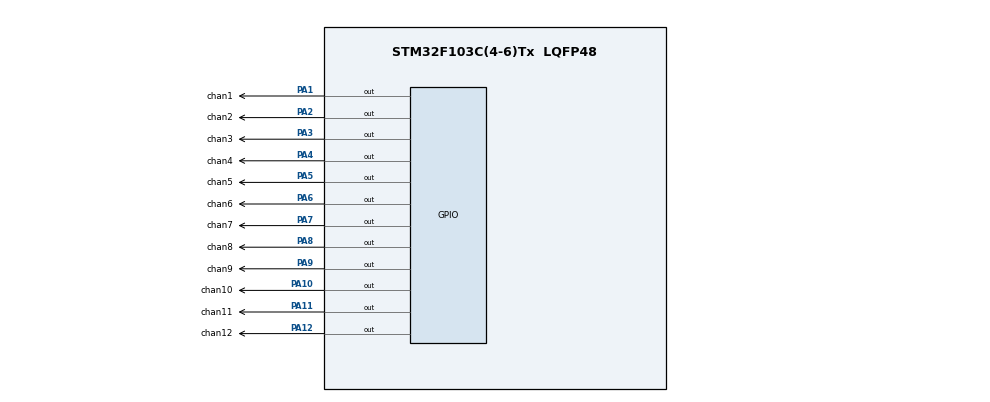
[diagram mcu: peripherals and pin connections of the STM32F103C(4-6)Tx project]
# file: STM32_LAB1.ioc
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Mcu.Family=STM32F1
Mcu.Name=STM32F103C(4-6)Tx
Mcu.Package=LQFP48
NVIC.PriorityGroup=NVIC_PRIORITYGROUP_4
PA1.GPIO_Label=chan1
PA1.Signal=GPIO_Output
PA10.GPIO_Label=chan10
PA10.Signal=GPIO_Output
PA11.GPIO_Label=chan11
PA11.Signal=GPIO_Output
PA12.GPIO_Label=chan12
PA12.Signal=GPIO_Output
PA2.GPIO_Label=chan2
PA2.Signal=GPIO_Output
PA3.GPIO_Label=chan3
PA3.Signal=GPIO_Output
PA4.GPIO_Label=chan4
PA4.Signal=GPIO_Output
PA5.GPIO_Label=chan5
PA5.Signal=GPIO_Output
PA6.GPIO_Label=chan6
PA6.Signal=GPIO_Output
PA7.GPIO_Label=chan7
PA7.Signal=GPIO_Output
PA8.GPIO_Label=chan8
PA8.Signal=GPIO_Output
PA9.GPIO_Label=chan9
PA9.Signal=GPIO_Output
ProjectManager.HeapSize=0x200
ProjectManager.StackSize=0x400
ProjectManager.TargetToolchain=STM32CubeIDE
RCC.APB1Freq_Value=8000000
RCC.APB2Freq_Value=8000000
board=custom

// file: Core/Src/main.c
/* USER CODE BEGIN Header */
/**
  ******************************************************************************
  * @file           : main.c
  * @brief          : Main program body
  ******************************************************************************
  * @attention
  *
  * Copyright (c) 2023 STMicroelectronics.
  * All rights reserved.
  *
  * This software is licensed under terms that can be found in the LICENSE file
  * in the root directory of this software component.
  * If no LICENSE file comes with this software, it is provided AS-IS.
  *
  ******************************************************************************
  */
/* USER CODE END Header */
#include "main.h"

void SystemClock_Config(void);
static void MX_GPIO_Init(void);

int main(void)
{

  /* MCU Configuration--------------------------------------------------------*/

  /* Reset of all peripherals, Initializes the Flash interface and the Systick. */
  HAL_Init();

  /* Configure the system clock */
  SystemClock_Config();

  /* Initialize all configured peripherals */
  MX_GPIO_Init();
  /* USER CODE BEGIN 2 */
  void do1()
{HAL_GPIO_WritePin(led_red1_GPIO_Port, led_red1_Pin,RESET);
 HAL_GPIO_WritePin(led_green1_GPIO_Port, led_green1_Pin,SET);
 HAL_GPIO_WritePin(led_yellow1_GPIO_Port, led_yellow1_Pin,SET);}
  void xanh1()
{
HAL_GPIO_WritePin(led_red1_GPIO_Port, led_red1_Pin,SET);
HAL_GPIO_WritePin(led_green1_GPIO_Port, led_green1_Pin,RESET);
HAL_GPIO_WritePin(led_yellow1_GPIO_Port, led_yellow1_Pin,SET);
}
  void vang1()
{HAL_GPIO_WritePin(led_red1_GPIO_Port, led_red1_Pin,SET);
 HAL_GPIO_WritePin(led_green1_GPIO_Port, led_green1_Pin,SET);
 HAL_GPIO_WritePin(led_yellow1_GPIO_Port, led_yellow1_Pin,RESET);
}
  void do2()
{HAL_GPIO_WritePin(led_red2_GPIO_Port, led_red2_Pin,RESET);
 HAL_GPIO_WritePin(led_green2_GPIO_Port, led_green2_Pin,SET);
 HAL_GPIO_WritePin(led_yellow2_GPIO_Port, led_yellow2_Pin,SET);}
  void xanh2()
{
HAL_GPIO_WritePin(led_red2_GPIO_Port, led_red2_Pin,SET);
HAL_GPIO_WritePin(led_green2_GPIO_Port, led_green2_Pin,RESET);
HAL_GPIO_WritePin(led_yellow2_GPIO_Port, led_yellow2_Pin,SET);
}
  void vang2()
{HAL_GPIO_WritePin(led_red2_GPIO_Port, led_red2_Pin,SET);
 HAL_GPIO_WritePin(led_green2_GPIO_Port, led_green2_Pin,SET);
 HAL_GPIO_WritePin(led_yellow2_GPIO_Port, led_yellow2_Pin,RESET);
}
  void display7SEGa(int n)
  {
  	switch (n)
  	{
  	case 0 :
  		HAL_GPIO_WritePin(chan1a_GPIO_Port,chan1a_Pin, RESET);
  		HAL_GPIO_WritePin(chan1b_GPIO_Port,chan1b_Pin, RESET);
  		HAL_GPIO_WritePin(chan1c_GPIO_Port,chan1c_Pin, RESET);
  		HAL_GPIO_WritePin(chan1d_GPIO_Port,chan1d_Pin, RESET);
  		HAL_GPIO_WritePin(chan1e_GPIO_Port,chan1e_Pin, RESET);
  		HAL_GPIO_WritePin(chan1f_GPIO_Port,chan1f_Pin, RESET);
  		HAL_GPIO_WritePin(chan1g_GPIO_Port,chan1g_Pin, SET);
  	    break ;
  	case 1 :
  		HAL_GPIO_WritePin(chan1a_GPIO_Port,chan1a_Pin, SET);
  		HAL_GPIO_WritePin(chan1b_GPIO_Port,chan1b_Pin, RESET);
  		HAL_GPIO_WritePin(chan1c_GPIO_Port,chan1c_Pin, RESET);
  		HAL_GPIO_WritePin(chan1d_GPIO_Port,chan1d_Pin, SET);
  		HAL_GPIO_WritePin(chan1e_GPIO_Port,chan1e_Pin, SET);
  		HAL_GPIO_WritePin(chan1f_GPIO_Port,chan1f_Pin, SET);
  		HAL_GPIO_WritePin(chan1g_GPIO_Port,chan1g_Pin, SET);
  	    break;
  	case 2 :
  		HAL_GPIO_WritePin(chan1a_GPIO_Port,chan1a_Pin, RESET);
  		HAL_GPIO_WritePin(chan1b_GPIO_Port,chan1b_Pin, RESET);
  		HAL_GPIO_WritePin(chan1c_GPIO_Port,chan1c_Pin, SET);
  		HAL_GPIO_WritePin(chan1d_GPIO_Port,chan1d_Pin, RESET);
  		HAL_GPIO_WritePin(chan1e_GPIO_Port,chan1e_Pin, RESET);
  		HAL_GPIO_WritePin(chan1f_GPIO_Port,chan1f_Pin, SET);
  		HAL_GPIO_WritePin(chan1g_GPIO_Port,chan1g_Pin, RESET);
  	    break ;
  	case 3 :
  		HAL_GPIO_WritePin(chan1a_GPIO_Port,chan1a_Pin, RESET);
  		HAL_GPIO_WritePin(chan1b_GPIO_Port,chan1b_Pin, RESET);
  		HAL_GPIO_WritePin(chan1c_GPIO_Port,chan1c_Pin, RESET);
  		HAL_GPIO_WritePin(chan1d_GPIO_Port,chan1d_Pin, RESET);
  		HAL_GPIO_WritePin(chan1e_GPIO_Port,chan1e_Pin, SET);
  		HAL_GPIO_WritePin(chan1f_GPIO_Port,chan1f_Pin, SET);
  		HAL_GPIO_WritePin(chan1g_GPIO_Port,chan1g_Pin, RESET);
  	    break ;
  	case 4 :
  		HAL_GPIO_WritePin(chan1a_GPIO_Port,chan1a_Pin, SET);
  		HAL_GPIO_WritePin(chan1b_GPIO_Port,chan1b_Pin, RESET);
  		HAL_GPIO_WritePin(chan1c_GPIO_Port,chan1c_Pin, RESET);
  		HAL_GPIO_WritePin(chan1d_GPIO_Port,chan1d_Pin, SET);
  		HAL_GPIO_WritePin(chan1e_GPIO_Port,chan1e_Pin, SET);
  		HAL_GPIO_WritePin(chan1f_GPIO_Port,chan1f_Pin, RESET);
  		HAL_GPIO_WritePin(chan1g_GPIO_Port,chan1g_Pin, RESET);
  		break ;
  	case 5 :
  		HAL_GPIO_WritePin(chan1a_GPIO_Port,chan1a_Pin, RESET);
  		HAL_GPIO_WritePin(chan1b_GPIO_Port,chan1b_Pin, SET);
  		HAL_GPIO_WritePin(chan1c_GPIO_Port,chan1c_Pin, RESET);
  		HAL_GPIO_WritePin(chan1d_GPIO_Port,chan1d_Pin, RESET);
  		HAL_GPIO_WritePin(chan1e_GPIO_Port,chan1e_Pin, SET);
  		HAL_GPIO_WritePin(chan1f_GPIO_Port,chan1f_Pin, RESET);
  		HAL_GPIO_WritePin(chan1g_GPIO_Port,chan1g_Pin, RESET);
  		break ;
  	case 6 :
  	  	HAL_GPIO_WritePin(chan1a_GPIO_Port,chan1a_Pin, RESET);
  	  	HAL_GPIO_WritePin(chan1b_GPIO_Port,chan1b_Pin, SET);
  	  	HAL_GPIO_WritePin(chan1c_GPIO_Port,chan1c_Pin, RESET);
  	  	HAL_GPIO_WritePin(chan1d_GPIO_Port,chan1d_Pin, RESET);
  	  	HAL_GPIO_WritePin(chan1e_GPIO_Port,chan1e_Pin, RESET);
  	  	HAL_GPIO_WritePin(chan1f_GPIO_Port,chan1f_Pin, RESET);
  	  	HAL_GPIO_WritePin(chan1g_GPIO_Port,chan1g_Pin, RESET);
  	  	break ;
  	default : break;

  	}
  }
  void display7SEGb(int n)
   {
   	switch (n)
   	{
   	case 0 :
   		HAL_GPIO_WritePin(chan2a_GPIO_Port,chan2a_Pin, RESET);
   		HAL_GPIO_WritePin(chan2b_GPIO_Port,chan2b_Pin, RESET);
   		HAL_GPIO_WritePin(chan2c_GPIO_Port,chan2c_Pin, RESET);
   		HAL_GPIO_WritePin(chan2d_GPIO_Port,chan2d_Pin, RESET);
   		HAL_GPIO_WritePin(chan2e_GPIO_Port,chan2e_Pin, RESET);
   		HAL_GPIO_WritePin(chan2f_GPIO_Port,chan2f_Pin, RESET);
   		HAL_GPIO_WritePin(chan2g_GPIO_Port,chan2g_Pin, SET);
   	    break ;
   	case 1 :
   		HAL_GPIO_WritePin(chan2a_GPIO_Port,chan2a_Pin, SET);
   		HAL_GPIO_WritePin(chan2b_GPIO_Port,chan2b_Pin, RESET);
   		HAL_GPIO_WritePin(chan2c_GPIO_Port,chan2c_Pin, RESET);
   		HAL_GPIO_WritePin(chan2d_GPIO_Port,chan2d_Pin, SET);
   		HAL_GPIO_WritePin(chan2e_GPIO_Port,chan2e_Pin, SET);
   		HAL_GPIO_WritePin(chan2f_GPIO_Port,chan2f_Pin, SET);
   		HAL_GPIO_WritePin(chan2g_GPIO_Port,chan2g_Pin, SET);
   	    break;
   	case 2 :
   		HAL_GPIO_WritePin(chan2a_GPIO_Port,chan2a_Pin, RESET);
   		HAL_GPIO_WritePin(chan2b_GPIO_Port,chan2b_Pin, RESET);
   		HAL_GPIO_WritePin(chan2c_GPIO_Port,chan2c_Pin, SET);
   		HAL_GPIO_WritePin(chan2d_GPIO_Port,chan2d_Pin, RESET);
   		HAL_GPIO_WritePin(chan2e_GPIO_Port,chan2e_Pin, RESET);
   		HAL_GPIO_WritePin(chan2f_GPIO_Port,chan2f_Pin, SET);
   		HAL_GPIO_WritePin(chan2g_GPIO_Port,chan2g_Pin, RESET);
   	    break ;
   	case 3 :
   		HAL_GPIO_WritePin(chan2a_GPIO_Port,chan2a_Pin, RESET);
   		HAL_GPIO_WritePin(chan2b_GPIO_Port,chan2b_Pin, RESET);
   		HAL_GPIO_WritePin(chan2c_GPIO_Port,chan2c_Pin, RESET);
   		HAL_GPIO_WritePin(chan2d_GPIO_Port,chan2d_Pin, RESET);
   		HAL_GPIO_WritePin(chan2e_GPIO_Port,chan2e_Pin, SET);
   		HAL_GPIO_WritePin(chan2f_GPIO_Port,chan2f_Pin, SET);
   		HAL_GPIO_WritePin(chan2g_GPIO_Port,chan2g_Pin, RESET);
   	    break ;
   	case 4 :
   		HAL_GPIO_WritePin(chan2a_GPIO_Port,chan2a_Pin, SET);
   		HAL_GPIO_WritePin(chan2b_GPIO_Port,chan2b_Pin, RESET);
   		HAL_GPIO_WritePin(chan2c_GPIO_Port,chan2c_Pin, RESET);
   		HAL_GPIO_WritePin(chan2d_GPIO_Port,chan2d_Pin, SET);
   		HAL_GPIO_WritePin(chan2e_GPIO_Port,chan2e_Pin, SET);
   		HAL_GPIO_WritePin(chan2f_GPIO_Port,chan2f_Pin, RESET);
   		HAL_GPIO_WritePin(chan2g_GPIO_Port,chan2g_Pin, RESET);
   		break ;
   	case 5 :
   		HAL_GPIO_WritePin(chan2a_GPIO_Port,chan2a_Pin, RESET);
   		HAL_GPIO_WritePin(chan2b_GPIO_Port,chan2b_Pin, SET);
   		HAL_GPIO_WritePin(chan2c_GPIO_Port,chan2c_Pin, RESET);
   		HAL_GPIO_WritePin(chan2d_GPIO_Port,chan2d_Pin, RESET);
   		HAL_GPIO_WritePin(chan2e_GPIO_Port,chan2e_Pin, SET);
   		HAL_GPIO_WritePin(chan2f_GPIO_Port,chan2f_Pin, RESET);
   		HAL_GPIO_WritePin(chan2g_GPIO_Port,chan2g_Pin, RESET);
   		break ;
   	case 6 :
   	   	HAL_GPIO_WritePin(chan2a_GPIO_Port,chan2a_Pin, RESET);
   	   	HAL_GPIO_WritePin(chan2b_GPIO_Port,chan2b_Pin, SET);
   	   	HAL_GPIO_WritePin(chan2c_GPIO_Port,chan2c_Pin, RESET);
   	   	HAL_GPIO_WritePin(chan2d_GPIO_Port,chan2d_Pin, RESET);
   	   	HAL_GPIO_WritePin(chan2e_GPIO_Port,chan2e_Pin, RESET);
   	   	HAL_GPIO_WritePin(chan2f_GPIO_Port,chan2f_Pin, RESET);
   	   	HAL_GPIO_WritePin(chan2g_GPIO_Port,chan2g_Pin, RESET);
   	   	break;
   	default : break;

   	}
   }

  /* USER CODE END 2 */
  int a,b;
  int i=1;
  /* Infinite loop */
  while (1)
  {
	  switch (i)
	  {
	  case 1 :
	  	do1();xanh2();
	  	for(a=5,b=3;b>=1;a--,b--)
	  	{
	  		display7SEGa(a);
	  		display7SEGb(b);
	  		HAL_Delay(1000);
	  	}
	  	break;
	  case 2 :
	  	do1();vang2();
	  	for(a=2,b=2;b>=1;a--,b--)
	  	{
	  		display7SEGa(a);
	  		display7SEGb(b);
	  		HAL_Delay(1000);
	  	}
	  	break;
	  case 3 :
	  	xanh1();do2();
	  	for(a=3,b=6;a>=1;a--,b--)
	  	{
	  		display7SEGa(a);
	  		display7SEGb(b);
	  		HAL_Delay(1000);
	  	}
	  	break;
	  case 4 : vang1();do2();
	  for(a=2,b=2;a>=1;a--,b--)
	  	{
	  		display7SEGa(a);
	  		display7SEGb(b);
	  		HAL_Delay(1000);
	  	}
	      i=0;break;
	  default : break;
	  }
	  i++;
  }
}

void SystemClock_Config(void)
{
  RCC_OscInitTypeDef RCC_OscInitStruct = {0};
  RCC_ClkInitTypeDef RCC_ClkInitStruct = {0};

  /** Initializes the RCC Oscillators according to the specified parameters
  * in the RCC_OscInitTypeDef structure.
  */
  RCC_OscInitStruct.OscillatorType = RCC_OSCILLATORTYPE_HSI;
  RCC_OscInitStruct.HSIState = RCC_HSI_ON;
  RCC_OscInitStruct.HSICalibrationValue = RCC_HSICALIBRATION_DEFAULT;
  RCC_OscInitStruct.PLL.PLLState = RCC_PLL_NONE;
  if (HAL_RCC_OscConfig(&RCC_OscInitStruct) != HAL_OK)
  {
    Error_Handler();
  }

  /** Initializes the CPU, AHB and APB buses clocks
  */
  RCC_ClkInitStruct.ClockType = RCC_CLOCKTYPE_HCLK|RCC_CLOCKTYPE_SYSCLK
                              |RCC_CLOCKTYPE_PCLK1|RCC_CLOCKTYPE_PCLK2;
  RCC_ClkInitStruct.SYSCLKSource = RCC_SYSCLKSOURCE_HSI;
  RCC_ClkInitStruct.AHBCLKDivider = RCC_SYSCLK_DIV1;
  RCC_ClkInitStruct.APB1CLKDivider = RCC_HCLK_DIV1;
  RCC_ClkInitStruct.APB2CLKDivider = RCC_HCLK_DIV1;

  if (HAL_RCC_ClockConfig(&RCC_ClkInitStruct, FLASH_LATENCY_0) != HAL_OK)
  {
    Error_Handler();
  }
}

static void MX_GPIO_Init(void)
{
  GPIO_InitTypeDef GPIO_InitStruct = {0};

  /* GPIO Ports Clock Enable */
  __HAL_RCC_GPIOA_CLK_ENABLE();
  __HAL_RCC_GPIOB_CLK_ENABLE();

  /*Configure GPIO pin Output Level */
  HAL_GPIO_WritePin(GPIOA, led_red1_Pin|led_yellow1_Pin|led_green1_Pin|led_red2_Pin
                          |led_yellow2_Pin|led_green2_Pin, GPIO_PIN_RESET);

  /*Configure GPIO pin Output Level */
  HAL_GPIO_WritePin(GPIOB, chan1a_Pin|chan1b_Pin|chan1c_Pin|chan2c_Pin
                          |chan2d_Pin|chan2e_Pin|chan2f_Pin|chan2g_Pin
                          |chan1d_Pin|chan1e_Pin|chan1f_Pin|chan1g_Pin
                          |chan2a_Pin|chan2b_Pin, GPIO_PIN_RESET);

  /*Configure GPIO pins : led_red1_Pin led_yellow1_Pin led_green1_Pin led_red2_Pin
                           led_yellow2_Pin led_green2_Pin */
  GPIO_InitStruct.Pin = led_red1_Pin|led_yellow1_Pin|led_green1_Pin|led_red2_Pin
                          |led_yellow2_Pin|led_green2_Pin;
  GPIO_InitStruct.Mode = GPIO_MODE_OUTPUT_PP;
  GPIO_InitStruct.Pull = GPIO_NOPULL;
  GPIO_InitStruct.Speed = GPIO_SPEED_FREQ_LOW;
  HAL_GPIO_Init(GPIOA, &GPIO_InitStruct);

  /*Configure GPIO pins : chan1a_Pin chan1b_Pin chan1c_Pin chan2c_Pin
                           chan2d_Pin chan2e_Pin chan2f_Pin chan2g_Pin
                           chan1d_Pin chan1e_Pin chan1f_Pin chan1g_Pin
                           chan2a_Pin chan2b_Pin */
  GPIO_InitStruct.Pin = chan1a_Pin|chan1b_Pin|chan1c_Pin|chan2c_Pin
                          |chan2d_Pin|chan2e_Pin|chan2f_Pin|chan2g_Pin
                          |chan1d_Pin|chan1e_Pin|chan1f_Pin|chan1g_Pin
                          |chan2a_Pin|chan2b_Pin;
  GPIO_InitStruct.Mode = GPIO_MODE_OUTPUT_PP;
  GPIO_InitStruct.Pull = GPIO_NOPULL;
  GPIO_InitStruct.Speed = GPIO_SPEED_FREQ_LOW;
  HAL_GPIO_Init(GPIOB, &GPIO_InitStruct);

}

void Error_Handler(void)
{
  __disable_irq();
  while (1)
  {
  }
}
